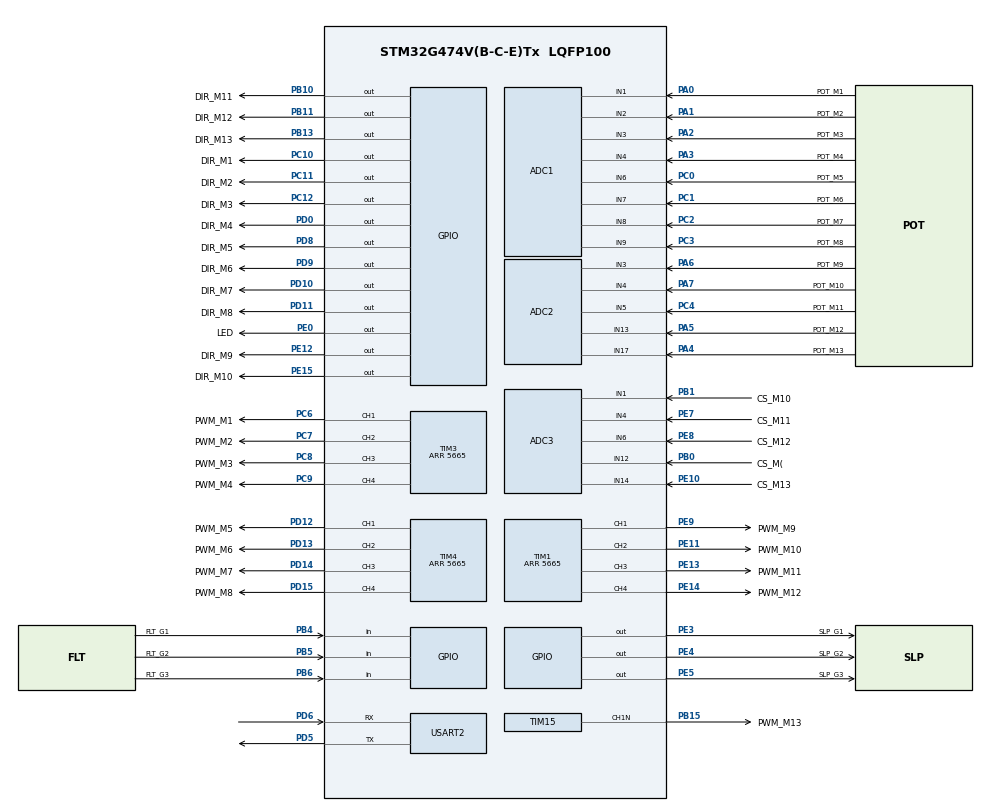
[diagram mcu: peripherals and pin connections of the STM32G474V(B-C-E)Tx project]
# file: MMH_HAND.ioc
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ADC1.Channel-0\#ChannelRegularConversion=ADC_CHANNEL_1
ADC1.Channel-1\#ChannelRegularConversion=ADC_CHANNEL_2
ADC1.Channel-2\#ChannelRegularConversion=ADC_CHANNEL_3
ADC1.Channel-3\#ChannelRegularConversion=ADC_CHANNEL_4
ADC1.Channel-4\#ChannelRegularConversion=ADC_CHANNEL_6
ADC1.Channel-5\#ChannelRegularConversion=ADC_CHANNEL_7
ADC1.Channel-6\#ChannelRegularConversion=ADC_CHANNEL_8
ADC1.Channel-7\#ChannelRegularConversion=ADC_CHANNEL_9
ADC1.ContinuousConvMode=ENABLE
ADC1.DMAContinuousRequests=ENABLE
ADC1.NbrOfConversion=8
ADC1.NbrOfConversionFlag=1
ADC1.OffsetNumber-0\#ChannelRegularConversion=ADC_OFFSET_NONE
ADC1.OffsetNumber-1\#ChannelRegularConversion=ADC_OFFSET_NONE
ADC1.OffsetNumber-2\#ChannelRegularConversion=ADC_OFFSET_NONE
ADC1.OffsetNumber-3\#ChannelRegularConversion=ADC_OFFSET_NONE
ADC1.OffsetNumber-4\#ChannelRegularConversion=ADC_OFFSET_NONE
ADC1.OffsetNumber-5\#ChannelRegularConversion=ADC_OFFSET_NONE
ADC1.OffsetNumber-6\#ChannelRegularConversion=ADC_OFFSET_NONE
ADC1.OffsetNumber-7\#ChannelRegularConversion=ADC_OFFSET_NONE
ADC1.Rank-0\#ChannelRegularConversion=1
ADC1.Rank-1\#ChannelRegularConversion=2
ADC1.Rank-2\#ChannelRegularConversion=3
ADC1.Rank-3\#ChannelRegularConversion=4
ADC1.Rank-4\#ChannelRegularConversion=5
ADC1.Rank-5\#ChannelRegularConversion=6
ADC1.Rank-6\#ChannelRegularConversion=7
ADC1.Rank-7\#ChannelRegularConversion=8
ADC1.SamplingTime-0\#ChannelRegularConversion=ADC_SAMPLETIME_247CYCLES_5
ADC1.SamplingTime-1\#ChannelRegularConversion=ADC_SAMPLETIME_247CYCLES_5
ADC1.SamplingTime-2\#ChannelRegularConversion=ADC_SAMPLETIME_247CYCLES_5
ADC1.SamplingTime-3\#ChannelRegularConversion=ADC_SAMPLETIME_247CYCLES_5
ADC1.SamplingTime-4\#ChannelRegularConversion=ADC_SAMPLETIME_247CYCLES_5
ADC1.SamplingTime-5\#ChannelRegularConversion=ADC_SAMPLETIME_247CYCLES_5
ADC1.SamplingTime-6\#ChannelRegularConversion=ADC_SAMPLETIME_247CYCLES_5
ADC1.SamplingTime-7\#ChannelRegularConversion=ADC_SAMPLETIME_247CYCLES_5
ADC1.master=1
ADC2.Channel-0\#ChannelRegularConversion=ADC_CHANNEL_3
ADC2.Channel-1\#ChannelRegularConversion=ADC_CHANNEL_4
ADC2.Channel-2\#ChannelRegularConversion=ADC_CHANNEL_5
ADC2.Channel-3\#ChannelRegularConversion=ADC_CHANNEL_13
ADC2.Channel-4\#ChannelRegularConversion=ADC_CHANNEL_17
ADC2.ContinuousConvMode=ENABLE
ADC2.DMAContinuousRequests=ENABLE
ADC2.NbrOfConversion=5
ADC2.NbrOfConversionFlag=1
ADC2.OffsetNumber-0\#ChannelRegularConversion=ADC_OFFSET_NONE
ADC2.OffsetNumber-1\#ChannelRegularConversion=ADC_OFFSET_NONE
ADC2.OffsetNumber-2\#ChannelRegularConversion=ADC_OFFSET_NONE
ADC2.OffsetNumber-3\#ChannelRegularConversion=ADC_OFFSET_NONE
ADC2.OffsetNumber-4\#ChannelRegularConversion=ADC_OFFSET_NONE
ADC2.Rank-0\#ChannelRegularConversion=1
ADC2.Rank-1\#ChannelRegularConversion=2
ADC2.Rank-2\#ChannelRegularConversion=3
ADC2.Rank-3\#ChannelRegularConversion=4
ADC2.Rank-4\#ChannelRegularConversion=5
ADC2.SamplingTime-0\#ChannelRegularConversion=ADC_SAMPLETIME_247CYCLES_5
ADC2.SamplingTime-1\#ChannelRegularConversion=ADC_SAMPLETIME_247CYCLES_5
ADC2.SamplingTime-2\#ChannelRegularConversion=ADC_SAMPLETIME_2CYCLES_5
ADC2.SamplingTime-3\#ChannelRegularConversion=ADC_SAMPLETIME_247CYCLES_5
ADC2.SamplingTime-4\#ChannelRegularConversion=ADC_SAMPLETIME_247CYCLES_5
ADC3.Channel-0\#ChannelRegularConversion=ADC_CHANNEL_12
ADC3.Channel-1\#ChannelRegularConversion=ADC_CHANNEL_1
ADC3.Channel-2\#ChannelRegularConversion=ADC_CHANNEL_4
ADC3.Channel-3\#ChannelRegularConversion=ADC_CHANNEL_6
ADC3.Channel-4\#ChannelRegularConversion=ADC_CHANNEL_14
ADC3.ContinuousConvMode=ENABLE
ADC3.DMAContinuousRequests=ENABLE
ADC3.NbrOfConversion=5
ADC3.NbrOfConversionFlag=1
ADC3.OffsetNumber-0\#ChannelRegularConversion=ADC_OFFSET_NONE
ADC3.OffsetNumber-1\#ChannelRegularConversion=ADC_OFFSET_NONE
ADC3.OffsetNumber-2\#ChannelRegularConversion=ADC_OFFSET_NONE
ADC3.OffsetNumber-3\#ChannelRegularConversion=ADC_OFFSET_NONE
ADC3.OffsetNumber-4\#ChannelRegularConversion=ADC_OFFSET_NONE
ADC3.Rank-0\#ChannelRegularConversion=1
ADC3.Rank-1\#ChannelRegularConversion=2
ADC3.Rank-2\#ChannelRegularConversion=3
ADC3.Rank-3\#ChannelRegularConversion=4
ADC3.Rank-4\#ChannelRegularConversion=5
ADC3.SamplingTime-0\#ChannelRegularConversion=ADC_SAMPLETIME_247CYCLES_5
ADC3.SamplingTime-1\#ChannelRegularConversion=ADC_SAMPLETIME_247CYCLES_5
ADC3.SamplingTime-2\#ChannelRegularConversion=ADC_SAMPLETIME_247CYCLES_5
ADC3.SamplingTime-3\#ChannelRegularConversion=ADC_SAMPLETIME_2CYCLES_5
ADC3.SamplingTime-4\#ChannelRegularConversion=ADC_SAMPLETIME_247CYCLES_5
ADC3.master=1
Dma.ADC1.0.Direction=DMA_PERIPH_TO_MEMORY
Dma.ADC1.0.EventEnable=DISABLE
Dma.ADC1.0.Instance=DMA2_Channel1
Dma.ADC1.0.MemDataAlignment=DMA_MDATAALIGN_HALFWORD
Dma.ADC1.0.MemInc=DMA_MINC_ENABLE
Dma.ADC1.0.Mode=DMA_CIRCULAR
Dma.ADC1.0.PeriphDataAlignment=DMA_PDATAALIGN_HALFWORD
Dma.ADC1.0.PeriphInc=DMA_PINC_DISABLE
Dma.ADC1.0.Polarity=HAL_DMAMUX_REQ_GEN_RISING
Dma.ADC1.0.Priority=DMA_PRIORITY_LOW
Dma.ADC1.0.RequestNumber=1
Dma.ADC1.0.SignalID=NONE
Dma.ADC1.0.SyncEnable=DISABLE
Dma.ADC1.0.SyncPolarity=HAL_DMAMUX_SYNC_NO_EVENT
Dma.ADC1.0.SyncRequestNumber=1
Dma.ADC1.0.SyncSignalID=NONE
Dma.ADC2.1.Direction=DMA_PERIPH_TO_MEMORY
Dma.ADC2.1.EventEnable=DISABLE
Dma.ADC2.1.Instance=DMA1_Channel2
Dma.ADC2.1.MemDataAlignment=DMA_MDATAALIGN_HALFWORD
Dma.ADC2.1.MemInc=DMA_MINC_ENABLE
Dma.ADC2.1.Mode=DMA_CIRCULAR
Dma.ADC2.1.PeriphDataAlignment=DMA_PDATAALIGN_HALFWORD
Dma.ADC2.1.PeriphInc=DMA_PINC_DISABLE
Dma.ADC2.1.Polarity=HAL_DMAMUX_REQ_GEN_RISING
Dma.ADC2.1.Priority=DMA_PRIORITY_LOW
Dma.ADC2.1.RequestNumber=1
Dma.ADC2.1.SignalID=NONE
Dma.ADC2.1.SyncEnable=DISABLE
Dma.ADC2.1.SyncPolarity=HAL_DMAMUX_SYNC_NO_EVENT
Dma.ADC2.1.SyncRequestNumber=1
Dma.ADC2.1.SyncSignalID=NONE
Dma.ADC3.2.Direction=DMA_PERIPH_TO_MEMORY
Dma.ADC3.2.EventEnable=DISABLE
Dma.ADC3.2.Instance=DMA1_Channel1
Dma.ADC3.2.MemDataAlignment=DMA_MDATAALIGN_HALFWORD
Dma.ADC3.2.MemInc=DMA_MINC_ENABLE
Dma.ADC3.2.Mode=DMA_CIRCULAR
Dma.ADC3.2.PeriphDataAlignment=DMA_PDATAALIGN_HALFWORD
Dma.ADC3.2.PeriphInc=DMA_PINC_DISABLE
Dma.ADC3.2.Polarity=HAL_DMAMUX_REQ_GEN_RISING
Dma.ADC3.2.Priority=DMA_PRIORITY_LOW
Dma.ADC3.2.RequestNumber=1
Dma.ADC3.2.SignalID=NONE
Dma.ADC3.2.SyncEnable=DISABLE
Dma.ADC3.2.SyncPolarity=HAL_DMAMUX_SYNC_NO_EVENT
Dma.ADC3.2.SyncRequestNumber=1
Dma.ADC3.2.SyncSignalID=NONE
Dma.Request0=ADC1
Dma.Request1=ADC2
Dma.Request2=ADC3
Dma.Request3=USART2_TX
Dma.USART2_TX.3.Direction=DMA_MEMORY_TO_PERIPH
Dma.USART2_TX.3.EventEnable=DISABLE
Dma.USART2_TX.3.Instance=DMA1_Channel3
Dma.USART2_TX.3.MemDataAlignment=DMA_MDATAALIGN_BYTE
Dma.USART2_TX.3.MemInc=DMA_MINC_ENABLE
Dma.USART2_TX.3.Mode=DMA_NORMAL
Dma.USART2_TX.3.PeriphDataAlignment=DMA_PDATAALIGN_BYTE
Dma.USART2_TX.3.PeriphInc=DMA_PINC_DISABLE
Dma.USART2_TX.3.Polarity=HAL_DMAMUX_REQ_GEN_RISING
Dma.USART2_TX.3.Priority=DMA_PRIORITY_LOW
Dma.USART2_TX.3.RequestNumber=1
Dma.USART2_TX.3.SignalID=NONE
Dma.USART2_TX.3.SyncEnable=DISABLE
Dma.USART2_TX.3.SyncPolarity=HAL_DMAMUX_SYNC_NO_EVENT
Dma.USART2_TX.3.SyncRequestNumber=1
Dma.USART2_TX.3.SyncSignalID=NONE
Mcu.Family=STM32G4
Mcu.Name=STM32G474V(B-C-E)Tx
Mcu.Package=LQFP100
NVIC.DMA1_Channel1_IRQn=true\:0\:0\:false\:false\:true\:false\:true
NVIC.DMA1_Channel2_IRQn=true\:0\:0\:false\:false\:true\:false\:true
NVIC.DMA1_Channel3_IRQn=true\:0\:0\:false\:false\:true\:false\:true
NVIC.DMA2_Channel1_IRQn=true\:0\:0\:false\:false\:true\:false\:true
NVIC.PriorityGroup=NVIC_PRIORITYGROUP_4
NVIC.USART2_IRQn=true\:0\:0\:false\:false\:true\:true\:true
PA0.GPIO_Label=POT_M1
PA0.Mode=IN1-Single-Ended
PA0.Signal=ADC1_IN1
PA1.GPIO_Label=POT_M2
PA1.Mode=IN2-Single-Ended
PA1.Signal=ADC1_IN2
PA13.Mode=Serial_Wire
PA13.Signal=SYS_JTMS-SWDIO
PA14.Mode=Serial_Wire
PA14.Signal=SYS_JTCK-SWCLK
PA2.GPIO_Label=POT_M3
PA2.Mode=IN3-Single-Ended
PA2.Signal=ADC1_IN3
PA3.GPIO_Label=POT_M4
PA3.Mode=IN4-Single-Ended
PA3.Signal=ADC1_IN4
PA4.GPIO_Label=POT_M13
PA4.Mode=IN17-Single-Ended
PA4.Signal=ADC2_IN17
PA5.GPIO_Label=POT_M12
PA5.Mode=IN13-Single-Ended
PA5.Signal=ADC2_IN13
PA6.GPIO_Label=POT_M9
PA6.Mode=IN3-Single-Ended
PA6.Signal=ADC2_IN3
PA7.GPIO_Label=POT_M10
PA7.Mode=IN4-Single-Ended
PA7.Signal=ADC2_IN4
PB0.GPIO_Label=CS_M(
PB0.Mode=IN12-Single-Ended
PB0.Signal=ADC3_IN12
PB1.GPIO_Label=CS_M10
PB1.Mode=IN1-Single-Ended
PB1.Signal=ADC3_IN1
PB10.GPIO_Label=DIR_M11
PB10.Signal=GPIO_Output
PB11.GPIO_Label=DIR_M12
PB11.Signal=GPIO_Output
PB13.GPIO_Label=DIR_M13
PB13.Signal=GPIO_Output
PB15.GPIO_Label=PWM_M13
PB15.Mode=PWM Generation1 CH1N
PB15.Signal=TIM15_CH1N
PB4.GPIO_Label=FLT_G1
PB4.Signal=GPIO_Input
PB5.GPIO_Label=FLT_G2
PB5.Signal=GPIO_Input
PB6.GPIO_Label=FLT_G3
PB6.Signal=GPIO_Input
PC0.GPIO_Label=POT_M5
PC0.Mode=IN6-Single-Ended
PC0.Signal=ADC1_IN6
PC1.GPIO_Label=POT_M6
PC1.Mode=IN7-Single-Ended
PC1.Signal=ADC1_IN7
PC10.GPIO_Label=DIR_M1
PC10.Signal=GPIO_Output
PC11.GPIO_Label=DIR_M2
PC11.Signal=GPIO_Output
PC12.GPIO_Label=DIR_M3
PC12.Signal=GPIO_Output
PC2.GPIO_Label=POT_M7
PC2.Mode=IN8-Single-Ended
PC2.Signal=ADC1_IN8
PC3.GPIO_Label=POT_M8
PC3.Mode=IN9-Single-Ended
PC3.Signal=ADC1_IN9
PC4.GPIO_Label=POT_M11
PC4.Mode=IN5-Single-Ended
PC4.Signal=ADC2_IN5
PC6.GPIO_Label=PWM_M1
PC6.Signal=S_TIM3_CH1
PC7.GPIO_Label=PWM_M2
PC7.Signal=S_TIM3_CH2
PC8.GPIO_Label=PWM_M3
PC8.Signal=S_TIM3_CH3
PC9.GPIO_Label=PWM_M4
PC9.Signal=S_TIM3_CH4
PD0.GPIO_Label=DIR_M4
PD0.Signal=GPIO_Output
PD10.GPIO_Label=DIR_M7
PD10.Signal=GPIO_Output
PD11.GPIO_Label=DIR_M8
PD11.Signal=GPIO_Output
PD12.GPIO_Label=PWM_M5
PD12.Signal=S_TIM4_CH1
PD13.GPIO_Label=PWM_M6
PD13.Signal=S_TIM4_CH2
PD14.GPIO_Label=PWM_M7
PD14.Signal=S_TIM4_CH3
PD15.GPIO_Label=PWM_M8
PD15.Signal=S_TIM4_CH4
PD5.Mode=Asynchronous
PD5.Signal=USART2_TX
PD6.Mode=Asynchronous
PD6.Signal=USART2_RX
PD8.GPIO_Label=DIR_M5
PD8.Signal=GPIO_Output
PD9.GPIO_Label=DIR_M6
PD9.Signal=GPIO_Output
PE0.GPIO_Label=LED
PE0.GPIO_PuPd=GPIO_NOPULL
PE0.Signal=GPIO_Output
PE10.GPIO_Label=CS_M13
PE10.Mode=IN14-Single-Ended
PE10.Signal=ADC3_IN14
PE11.GPIO_Label=PWM_M10
PE11.Signal=S_TIM1_CH2
PE12.GPIO_Label=DIR_M9
PE12.Signal=GPIO_Output
PE13.GPIO_Label=PWM_M11
PE13.Signal=S_TIM1_CH3
PE14.GPIO_Label=PWM_M12
PE14.Signal=S_TIM1_CH4
PE15.GPIO_Label=DIR_M10
PE15.Signal=GPIO_Output
PE3.GPIO_Label=SLP_G1
PE3.Signal=GPIO_Output
PE4.GPIO_Label=SLP_G2
PE4.Signal=GPIO_Output
PE5.GPIO_Label=SLP_G3
PE5.Signal=GPIO_Output
PE7.GPIO_Label=CS_M11
PE7.Mode=IN4-Single-Ended
PE7.Signal=ADC3_IN4
PE8.GPIO_Label=CS_M12
PE8.Mode=IN6-Single-Ended
PE8.Signal=ADC3_IN6
PE9.GPIO_Label=PWM_M9
PE9.Signal=S_TIM1_CH1
ProjectManager.HeapSize=0x200
ProjectManager.StackSize=0x400
ProjectManager.TargetToolchain=STM32CubeIDE
RCC.AHBFreq_Value=16000000
RCC.APB1Freq_Value=16000000
RCC.APB1TimFreq_Value=16000000
RCC.APB2Freq_Value=16000000
RCC.APB2TimFreq_Value=16000000
RCC.CortexFreq_Value=16000000
RCC.EXTERNAL_CLOCK_VALUE=12288000
RCC.HCLKFreq_Value=16000000
RCC.HSE_VALUE=8000000
RCC.HSI48_VALUE=48000000
RCC.HSI_VALUE=16000000
RCC.LSE_VALUE=32768
RCC.SYSCLKFreq_VALUE=16000000
RCC.USBFreq_Value=64000000
RCC.VCOOutputFreq_Value=128000000
SH.S_TIM1_CH1.0=TIM1_CH1,PWM Generation1 CH1
SH.S_TIM1_CH2.0=TIM1_CH2,PWM Generation2 CH2
SH.S_TIM1_CH3.0=TIM1_CH3,PWM Generation3 CH3
SH.S_TIM1_CH4.0=TIM1_CH4,PWM Generation4 CH4
SH.S_TIM3_CH1.0=TIM3_CH1,PWM Generation1 CH1
SH.S_TIM3_CH2.0=TIM3_CH2,PWM Generation2 CH2
SH.S_TIM3_CH3.0=TIM3_CH3,PWM Generation3 CH3
SH.S_TIM3_CH4.0=TIM3_CH4,PWM Generation4 CH4
SH.S_TIM4_CH1.0=TIM4_CH1,PWM Generation1 CH1
SH.S_TIM4_CH2.0=TIM4_CH2,PWM Generation2 CH2
SH.S_TIM4_CH3.0=TIM4_CH3,PWM Generation3 CH3
SH.S_TIM4_CH4.0=TIM4_CH4,PWM Generation4 CH4
TIM1.AutoReloadPreload=TIM_AUTORELOAD_PRELOAD_ENABLE
TIM1.Channel-PWM\ Generation1\ CH1=TIM_CHANNEL_1
TIM1.Channel-PWM\ Generation2\ CH2=TIM_CHANNEL_2
TIM1.Channel-PWM\ Generation3\ CH3=TIM_CHANNEL_3
TIM1.Channel-PWM\ Generation4\ CH4=TIM_CHANNEL_4
TIM1.PeriodNoDither=5665
TIM15.AutoReloadPreload=TIM_AUTORELOAD_PRELOAD_ENABLE
TIM15.Channel-PWM\ Generation1\ CH1N=TIM_CHANNEL_1
TIM15.OCNPolarity_1=TIM_OCNPOLARITY_HIGH
TIM15.PeriodNoDither=5665
TIM3.AutoReloadPreload=TIM_AUTORELOAD_PRELOAD_ENABLE
TIM3.Channel-PWM\ Generation1\ CH1=TIM_CHANNEL_1
TIM3.Channel-PWM\ Generation2\ CH2=TIM_CHANNEL_2
TIM3.Channel-PWM\ Generation3\ CH3=TIM_CHANNEL_3
TIM3.Channel-PWM\ Generation4\ CH4=TIM_CHANNEL_4
TIM3.PeriodNoDither=5665
TIM4.AutoReloadPreload=TIM_AUTORELOAD_PRELOAD_ENABLE
TIM4.Channel-PWM\ Generation1\ CH1=TIM_CHANNEL_1
TIM4.Channel-PWM\ Generation2\ CH2=TIM_CHANNEL_2
TIM4.Channel-PWM\ Generation3\ CH3=TIM_CHANNEL_3
TIM4.Channel-PWM\ Generation4\ CH4=TIM_CHANNEL_4
TIM4.PeriodNoDither=5665
USART2.VirtualMode-Asynchronous=VM_ASYNC
VP_SYS_VS_DBSignals.Mode=DisableDeadBatterySignals
board=custom

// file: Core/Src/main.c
#include "main.h"
#include "adc.h"
#include "dma.h"
#include "usart.h"
#include "tim.h"
#include "gpio.h"
#include <math.h>

/* USER CODE BEGIN Includes */
#include "hand_config.h"
#include "hand_sensor.h"
#include "hand_motor.h"  // <-- 이 헤더파일이 정상적으로 들어있어야 합니다!
/* USER CODE END Includes */

// [NEW] 새로운 DMA 버퍼 크기 매핑
volatile uint16_t adc1_buf[8], adc2_buf[5], adc3_buf[5];

uint8_t system_state = 1;
uint8_t grip_step = 0;
uint32_t step_timer = 0;
static uint8_t state4_step = 0;
static uint32_t state4_timer = 0;
static uint8_t state5_step = 0;

uint8_t bit_2 = 0;

void SystemClock_Config(void);

int main(void)
{
  HAL_Init();
  SystemClock_Config();

  MX_GPIO_Init();
  MX_DMA_Init();
  MX_ADC1_Init();
  MX_ADC2_Init();
  MX_ADC3_Init();
  MX_USART2_UART_Init();
  MX_TIM1_Init();
  MX_TIM3_Init();
  MX_TIM4_Init();
  MX_TIM15_Init();

  // [NEW] 1. ADC DMA 시작 (크기 변경)
  HAL_ADC_Start_DMA(&hadc1, (uint32_t*)adc1_buf, 8);
  HAL_ADC_Start_DMA(&hadc2, (uint32_t*)adc2_buf, 5);
  HAL_ADC_Start_DMA(&hadc3, (uint32_t*)adc3_buf, 5);

  HAL_Delay(50);

  // [NEW] 2. 모터 드라이버 Sleep 해제 (Wake up)
  HAL_GPIO_WritePin(GPIOE, GPIO_PIN_3, GPIO_PIN_SET);
  HAL_GPIO_WritePin(GPIOE, GPIO_PIN_4, GPIO_PIN_SET);
  HAL_GPIO_WritePin(GPIOE, GPIO_PIN_5, GPIO_PIN_SET);

  // 3. 센서 업데이트 및 모터 구조체 초기화
  Hand_Sensor_Update();
  Hand_Motor_Init();

  // [NEW] 4. 새로운 타이머 채널 PWM 시작
  HAL_TIM_PWM_Start(&htim3, TIM_CHANNEL_1); HAL_TIM_PWM_Start(&htim3, TIM_CHANNEL_2);
  HAL_TIM_PWM_Start(&htim3, TIM_CHANNEL_3); HAL_TIM_PWM_Start(&htim3, TIM_CHANNEL_4);
  HAL_TIM_PWM_Start(&htim4, TIM_CHANNEL_1); HAL_TIM_PWM_Start(&htim4, TIM_CHANNEL_2);
  HAL_TIM_PWM_Start(&htim4, TIM_CHANNEL_3); HAL_TIM_PWM_Start(&htim4, TIM_CHANNEL_4);
  HAL_TIM_PWM_Start(&htim1, TIM_CHANNEL_1); HAL_TIM_PWM_Start(&htim1, TIM_CHANNEL_2);
  HAL_TIM_PWM_Start(&htim1, TIM_CHANNEL_3); HAL_TIM_PWM_Start(&htim1, TIM_CHANNEL_4);
  HAL_TIMEx_PWMN_Start(&htim15, TIM_CHANNEL_1);

  while (1) {
      Hand_Sensor_Update();

      // =========================================================
      // 여기에 기존에 작성하신 if (system_state == 0) ~ else if (system_state == 5)
      // 시퀀스 코드를 100% 동일하게 그대로 복사해서 넣으시면 됩니다.
      // (기존 모션 로직 완벽 호환됨)
      // =========================================================

      // --- [시스템 상태 제어] ---
      if (system_state == 0) {
          // 자유 모드: Live Watch 조작 대기
          grip_step = 0;
      }
      else if (system_state == 1) {
          // 홈 모드: 초기 위치 고정
          for (int i = 1; i <= 13; i++) {
              motors[i].target_angle = motors[i].init_angle;
              motors[i].control_mode = 1;
          }
          grip_step = 0;
      }

      else if (system_state == 4) {
                // =========================================================
                // [REVISED] 손 벌려 잡은 후, 2초 뒤 한 번 더 쥐어짜는 시나리오
                // =========================================================

                // [Step 0] 초기화 및 제어 모드 설정
    	  if (state4_step == 0) {
    	                // 스텝 1, 3에서 움직일 관절들을 궤적 모드(2)로 세팅하여 부드럽게 기동
    	                int target_joints[] = {1, 2, 3, 4, 5, 6, 7, 8};
    	                for (int j = 0; j < 8; j++) {
    	                    int m_idx = target_joints[j];   // [수정] 빠졌던 변수 선언 추가
    	                    motors[m_idx].control_mode = 2; // 부드러운 궤적 제어
    	                }
    	                for (int j = 9; j <= 12; j++) {
    	                    motors[j].control_mode = 1; // 와이어는 일반 위치 제어 시작
    	                }

    	                state4_timer = HAL_GetTick();
    	                state4_step = 1;
    	            }

                // [Step 1] 손가락 쫙 벌려 물체 감싸기
                else if (state4_step == 1) {
                    motors[1].target_angle = 10.0f;  // 90 -> 10
                    motors[3].target_angle = 20.0f;  // 50 -> 20
                    motors[5].target_angle = 25.0f;  // 25 유지
                    motors[7].target_angle = 50.0f;  // 30 -> 50

                    if (fabsf(motors[1].error) < 4.0f && fabsf(motors[3].error) < 4.0f &&
                        fabsf(motors[7].error) < 4.0f)
                    {
                        state4_timer = HAL_GetTick();
                        state4_step = 2; // 스텝 2로 이동
                    }
                }

                // [Step 2] 와이어 모터 상수 힘 제어(모드 3) 전환 후 2초 대기
    	  // [Step 2] 와이어 모터 상수 힘 제어(모드 3) 전환 (M10은 1초 늦게 시작) 후 2초 대기
    	            else if (state4_step == 2) {
    	                // 1. 9, 11, 12번 와이어는 진입 즉시 모드 3으로 전환
    	                motors[9].control_mode = 3;
    	                motors[11].control_mode = 3;
    	                motors[12].control_mode = 3;

    	                // 2. 10번 와이어는 스텝 2 시작 후 1초(1000ms)가 지난 후에 모드 3으로 전환
    	                if (HAL_GetTick() - state4_timer >= 500) {
    	                    motors[10].control_mode = 3;
    	                }
    	                else {
    	                    // 1초가 되기 전까지는 안전하게 기존 위치 제어 모드(1)를 유지
    	                    motors[10].control_mode = 1;
    	                }

    	                // 3. 스텝 2 전체 대기 시간은 여전히 2초(2000ms) 유지 후 스텝 3으로 이동
    	                if (HAL_GetTick() - state4_timer > 1000) {
    	                    state4_timer = HAL_GetTick();
    	                    state4_step = 3; // 스텝 3으로 이동
    	                }
    	            }

                // [Step 3] 1차 움켜쥐기
                else if (state4_step == 3) {
                    motors[2].target_angle = 70.0f;  // 90 -> 70
                    motors[4].target_angle = 70.0f;  // 30 -> 70
                    motors[6].target_angle = 80.0f;  // 30 -> 80
                    motors[8].target_angle = 40.0f;  // 85 -> 40

                    // 1차 움켜쥐기 관절들이 모두 목적지에 도달했는지 확인
                    if (fabsf(motors[2].error) < 4.0f && fabsf(motors[4].error) < 4.0f &&
                        fabsf(motors[6].error) < 4.0f && fabsf(motors[8].error) < 4.0f)
                    {
                        state4_timer = HAL_GetTick(); // 도달한 순간부터 스톱워치 시작
                        state4_step = 4;              // [NEW] 스텝 4(2초 대기 구간)로 이동
                    }
                }

                // [Step 4] 1차 움켜쥐기 완료 후 2초간 대기 플래그
                else if (state4_step == 4) {
                    // 스텝 3 도달 후 딱 2초(2000ms)가 지나면 다음 스텝 실행
                    if (HAL_GetTick() - state4_timer > 2000) {
                        state4_timer = HAL_GetTick();
                        state4_step = 5; // [NEW] 스텝 5(최종 쥐어짜기)로 이동
                    }
                }

                // [Step 5] 2차 최종 쥐어짜기 (더 강력한 압박)
    	  // [Step 5] 2차 최종 쥐어짜기 (더 강력한 압박)
    	            else if (state4_step == 5) {
    	                // 물체가 손에 걸려서 에러가 크게 남더라도, 일단 모터는 계속 힘을 주며 압박합니다.
    	                motors[2].target_angle = 30.0f;
    	                motors[4].target_angle = 90.0f;
    	                motors[6].target_angle = 90.0f;
    	                motors[8].target_angle = 30.0f;

    	                // ---------------------------------------------------------
    	                // [수정 포인트] 도달 조건문 바깥으로 비트 감지 로직을 꺼냈습니다.
    	                // 이제 손가락 오차(에러)와 무관하게, 스텝 5 상태라면
    	                // 라이브 워치에서 비트를 켜는 순간 '즉시' 반응합니다.
    	                // ---------------------------------------------------------
    	                if (bit_2 != 0) {
    	                    state4_timer = HAL_GetTick(); // 스텝 6용 타이머 시작
    	                    state4_step = 6;              // 즉시 스텝 6으로 점프!
    	                }
    	            }

    	            // [Step 6] M13 구조 재조정 (160도 -> 50도 이동)
    	            else if (state4_step == 6) {
    	                // M13 모터를 빠른 위치제어 모드(1)로 설정하고 목표각도 50도 부여
    	                motors[13].control_mode = 1;
    	                motors[13].target_angle = 50.0f;
    	                motors[9].control_mode = 4;
    	                motors[10].control_mode = 4;
    	                motors[11].control_mode = 4;
    	                motors[12].control_mode = 4;

    	                // 오차 계산
    	                float m13_error = fabsf(motors[13].target_angle - motors[13].current_angle);

    	                // 50도 근처에 도달했거나, 기계적 걸림을 대비해 2초(2000ms) 타임아웃 시 종료
    	                if (m13_error < 4.0f || (HAL_GetTick() - state4_timer > 2000)) {
    	                    // [선택] 완전히 동작을 끝내고 손을 풀려면 아래 주석을 해제하여 홈 모드로 보냅니다.
    	                    // system_state = 1;

    	                }
    	            }
            }

      // 안전장치: 상태 5가 아닐 때는 항상 단계를 0으로 초기화
      if (system_state != 5) state5_step = 0;

      Hand_Motor_PID_Compute();
      Hand_Motor_Drive();

      HAL_Delay(10); // 기존 제어 주기 유지
  }
}

void SystemClock_Config(void)
{
  RCC_OscInitTypeDef RCC_OscInitStruct = {0};
  RCC_ClkInitTypeDef RCC_ClkInitStruct = {0};
  RCC_PeriphCLKInitTypeDef PeriphClkInit = {0};

  /** Configure the main internal regulator output voltage
  */
  HAL_PWREx_ControlVoltageScaling(PWR_REGULATOR_VOLTAGE_SCALE1_BOOST);
  /** Initializes the RCC Oscillators according to the specified parameters
  * in the RCC_OscInitTypeDef structure.
  */
  RCC_OscInitStruct.OscillatorType = RCC_OSCILLATORTYPE_HSI;
  RCC_OscInitStruct.HSIState = RCC_HSI_ON;
  RCC_OscInitStruct.HSICalibrationValue = RCC_HSICALIBRATION_DEFAULT;
  RCC_OscInitStruct.PLL.PLLState = RCC_PLL_ON;
  RCC_OscInitStruct.PLL.PLLSource = RCC_PLLSOURCE_HSI;
  RCC_OscInitStruct.PLL.PLLM = RCC_PLLM_DIV4;
  RCC_OscInitStruct.PLL.PLLN = 85;
  RCC_OscInitStruct.PLL.PLLP = RCC_PLLP_DIV2;
  RCC_OscInitStruct.PLL.PLLQ = RCC_PLLQ_DIV2;
  RCC_OscInitStruct.PLL.PLLR = RCC_PLLR_DIV2;
  if (HAL_RCC_OscConfig(&RCC_OscInitStruct) != HAL_OK)
  {
    Error_Handler();
  }
  /** Initializes the CPU, AHB and APB buses clocks
  */
  RCC_ClkInitStruct.ClockType = RCC_CLOCKTYPE_HCLK|RCC_CLOCKTYPE_SYSCLK
                              |RCC_CLOCKTYPE_PCLK1|RCC_CLOCKTYPE_PCLK2;
  RCC_ClkInitStruct.SYSCLKSource = RCC_SYSCLKSOURCE_PLLCLK;
  RCC_ClkInitStruct.AHBCLKDivider = RCC_SYSCLK_DIV1;
  RCC_ClkInitStruct.APB1CLKDivider = RCC_HCLK_DIV1;
  RCC_ClkInitStruct.APB2CLKDivider = RCC_HCLK_DIV1;

  if (HAL_RCC_ClockConfig(&RCC_ClkInitStruct, FLASH_LATENCY_4) != HAL_OK)
  {
    Error_Handler();
  }
  /** Initializes the peripherals clocks
  */
  PeriphClkInit.PeriphClockSelection = RCC_PERIPHCLK_LPUART1|RCC_PERIPHCLK_ADC12
                              |RCC_PERIPHCLK_ADC345;
  PeriphClkInit.Lpuart1ClockSelection = RCC_LPUART1CLKSOURCE_PCLK1;
  PeriphClkInit.Adc12ClockSelection = RCC_ADC12CLKSOURCE_SYSCLK;
  PeriphClkInit.Adc345ClockSelection = RCC_ADC345CLKSOURCE_SYSCLK;
  if (HAL_RCCEx_PeriphCLKConfig(&PeriphClkInit) != HAL_OK)
  {
    Error_Handler();
  }
}

void Error_Handler(void)
{
  __disable_irq();
  while (1)
  {
  }
}

/************************ (C) COPYRIGHT STMicroelectronics *****END OF FILE****/
